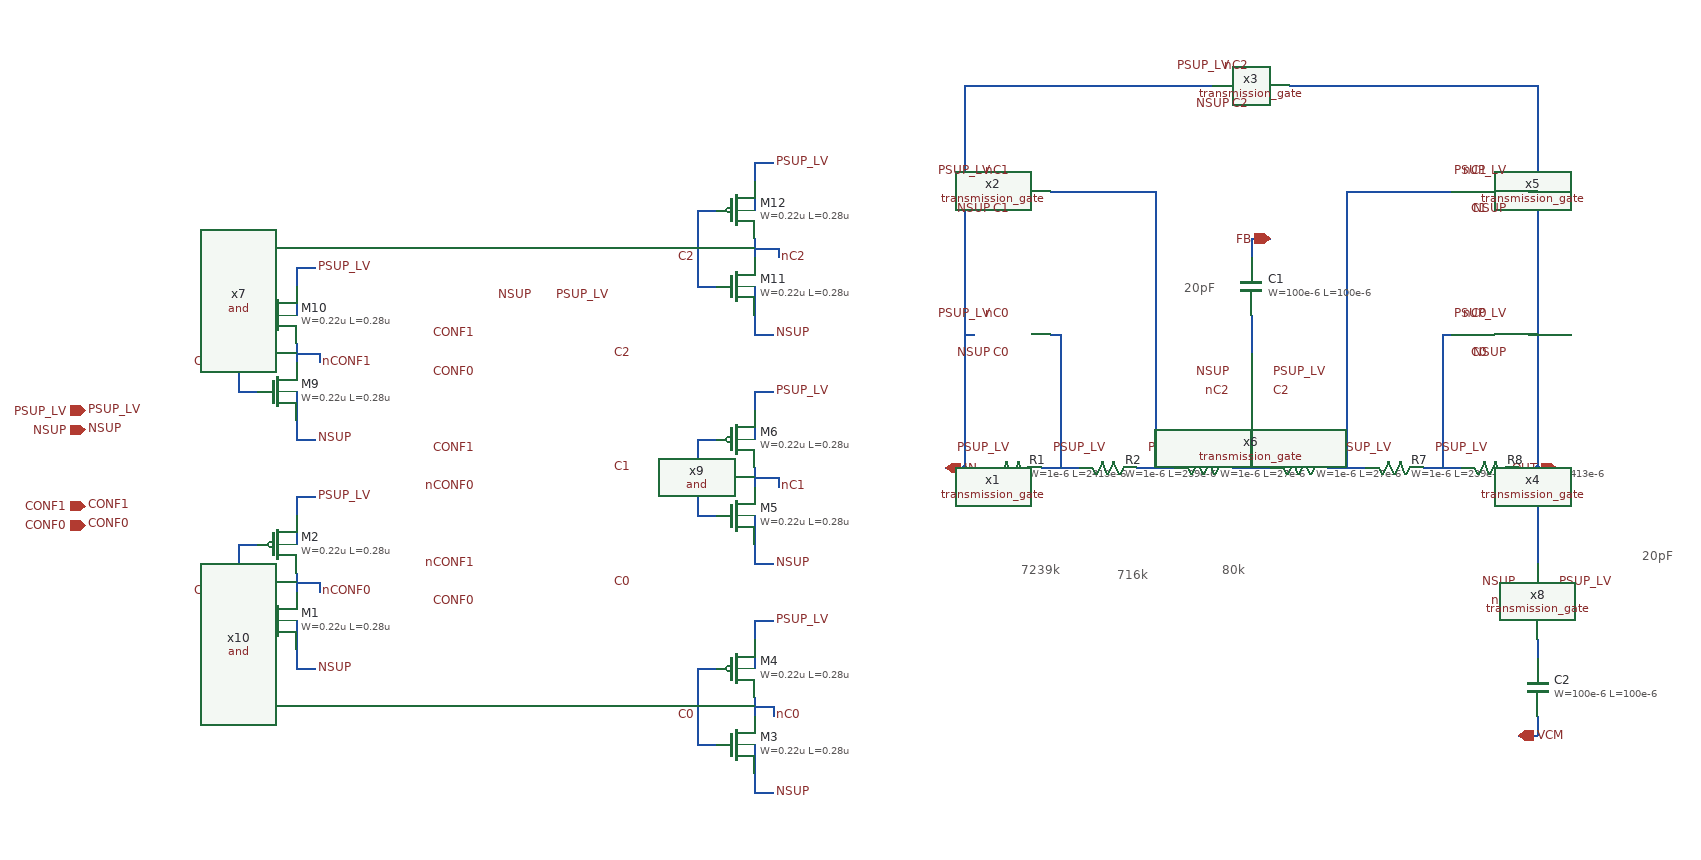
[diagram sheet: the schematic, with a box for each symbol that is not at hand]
v {xschem version=3.4.7 file_version=1.2}
G {}
K {}
V {}
S {}
E {}
T {20pF} 670 -200 0 0 0.4 0.4 {}
T {20pF} 1150 80 0 0 0.4 0.4 {}
T {80k} 710 95 1 0 0.4 0.4 {}
T {716k} 600 100 1 0 0.4 0.4 {}
T {7239k} 500 95 1 0 0.4 0.4 {}
N -320 -160 -300 -160 {lab=CONF1}
N -320 -160 -320 -80 {lab=CONF1}
N -320 -80 -300 -80 {lab=CONF1}
N -260 -130 -260 -110 {lab=nCONF1}
N -260 -120 -235 -120 {lab=nCONF1}
N -235 -120 -235 -110 {lab=nCONF1}
N -260 -210 -240 -210 {lab=PSUP_LV}
N -260 -210 -260 -190 {lab=PSUP_LV}
N -260 -30 -240 -30 {lab=NSUP}
N -260 -50 -260 -30 {lab=NSUP}
N -260 -80 -260 -50 {lab=NSUP}
N -260 -190 -260 -160 {lab=PSUP_LV}
N -320 80 -300 80 {lab=CONF0}
N -320 80 -320 160 {lab=CONF0}
N -320 160 -300 160 {lab=CONF0}
N -260 110 -260 130 {lab=nCONF0}
N -260 120 -235 120 {lab=nCONF0}
N -235 120 -235 130 {lab=nCONF0}
N -260 30 -240 30 {lab=PSUP_LV}
N -260 30 -260 50 {lab=PSUP_LV}
N -260 210 -240 210 {lab=NSUP}
N -260 190 -260 210 {lab=NSUP}
N -260 160 -260 190 {lab=NSUP}
N -260 50 -260 80 {lab=PSUP_LV}
N 740 -240 760 -240 {lab=FB}
N 740 -240 740 -220 {lab=FB}
N 1020 280 1040 280 {lab=VCM}
N 1040 260 1040 280 {lab=VCM}
N 1020 0 1040 0 {lab=OUT}
N 920 0 960 0 {lab=#net1}
N 820 0 860 0 {lab=#net2}
N 720 0 760 0 {lab=#net3}
N 620 0 660 0 {lab=#net4}
N 520 0 560 0 {lab=#net5}
N 1040 0 1040 60 {lab=OUT}
N 1040 0 1060 0 {lab=OUT}
N 440 0 460 0 {lab=IN}
N 160 210 180 210 {lab=C0}
N 160 210 160 290 {lab=C0}
N 160 290 180 290 {lab=C0}
N 220 240 220 260 {lab=nC0}
N 240 250 240 260 {lab=nC0}
N 220 160 240 160 {lab=PSUP_LV}
N 220 160 220 180 {lab=PSUP_LV}
N 220 340 240 340 {lab=NSUP}
N 220 320 220 340 {lab=NSUP}
N 160 -30 180 -30 {lab=C1}
N 160 -30 160 50 {lab=C1}
N 160 50 180 50 {lab=C1}
N 220 0 220 20 {lab=nC1}
N 220 10 245 10 {lab=nC1}
N 245 10 245 20 {lab=nC1}
N 220 -80 240 -80 {lab=PSUP_LV}
N 220 -80 220 -60 {lab=PSUP_LV}
N 220 100 240 100 {lab=NSUP}
N 220 80 220 100 {lab=NSUP}
N 160 -270 180 -270 {lab=C2}
N 160 -270 160 -190 {lab=C2}
N 160 -190 180 -190 {lab=C2}
N 220 -240 220 -220 {lab=nC2}
N 220 -230 245 -230 {lab=nC2}
N 245 -230 245 -220 {lab=nC2}
N 220 -320 240 -320 {lab=PSUP_LV}
N 220 -320 220 -300 {lab=PSUP_LV}
N 220 -140 240 -140 {lab=NSUP}
N 220 -160 220 -140 {lab=NSUP}
N 220 290 220 320 {lab=NSUP}
N 220 180 220 210 {lab=PSUP_LV}
N 220 -60 220 -30 {lab=PSUP_LV}
N 220 50 220 80 {lab=NSUP}
N 220 -300 220 -270 {lab=PSUP_LV}
N 220 -190 220 -160 {lab=NSUP}
N 220 250 240 250 {lab=nC0}
N 420 0 440 0 {lab=IN}
N 440 -270 440 0 {lab=IN}
N 440 -140 450 -140 {lab=IN}
N 440 -400 440 -270 {lab=IN}
N 1040 -400 1040 0 {lab=OUT}
N 440 -400 700 -400 {lab=IN}
N 780 -400 1040 -400 {lab=OUT}
N 440 -290 450 -290 {lab=IN}
N 940 -140 950 -140 {lab=#net1}
N 940 -140 940 0 {lab=#net1}
N 1030 -140 1040 -140 {lab=OUT}
N 840 -270 840 0 {lab=#net2}
N 1030 -290 1040 -290 {lab=OUT}
N 840 -290 950 -290 {lab=#net2}
N 840 -290 840 -270 {lab=#net2}
N 440 -140 450 -140 {lab=IN}
N 440 -290 450 -290 {lab=IN}
N 740 -160 740 -140 {lab=#net6}
N 740 -140 740 -120 {lab=#net6}
N 740 -40 740 0 {lab=#net3}
N 530 -140 540 -140 {lab=#net5}
N 540 -140 540 0 {lab=#net5}
N 640 -290 640 0 {lab=#net4}
N 620 -290 640 -290 {lab=#net4}
N 530 -290 620 -290 {lab=#net4}
N 1040 60 1040 100 {lab=OUT}
N 1040 180 1040 200 {lab=#net7}
C {ipin.sym} -480 -60 0 0 {name=p6 lab=PSUP_LV}
C {ipin.sym} -480 -40 0 0 {name=p7 lab=NSUP}
C {ipin.sym} -480 40 0 0 {name=p4 lab=CONF1}
C {lab_wire.sym} -480 -40 0 1 {name=p12 sig_type=std_logic lab=NSUP}
C {lab_wire.sym} -480 40 0 1 {name=p15 sig_type=std_logic lab=CONF1}
C {lab_wire.sym} -480 -60 0 1 {name=p13 sig_type=std_logic lab=PSUP_LV}
C {ipin.sym} -480 60 0 0 {name=p14 lab=CONF0}
C {lab_wire.sym} -480 60 0 1 {name=p17 sig_type=std_logic lab=CONF0}
C {symbols/nfet_03v3.sym} -280 -80 0 0 {name=M9
L=0.28u
W=0.22u
nf=1
m=1
ad="'int((nf+1)/2) * W/nf * 0.18u'"
pd="'2*int((nf+1)/2) * (W/nf + 0.18u)'"
as="'int((nf+2)/2) * W/nf * 0.18u'"
ps="'2*int((nf+2)/2) * (W/nf + 0.18u)'"
nrd="'0.18u / W'" nrs="'0.18u / W'"
sa=0 sb=0 sd=0
model=nfet_03v3
spiceprefix=X
}
C {symbols/pfet_03v3.sym} -280 -160 0 0 {name=M10
L=0.28u
W=0.22u
nf=1
m=1
ad="'int((nf+1)/2) * W/nf * 0.18u'"
pd="'2*int((nf+1)/2) * (W/nf + 0.18u)'"
as="'int((nf+2)/2) * W/nf * 0.18u'"
ps="'2*int((nf+2)/2) * (W/nf + 0.18u)'"
nrd="'0.18u / W'" nrs="'0.18u / W'"
sa=0 sb=0 sd=0
model=pfet_03v3
spiceprefix=X
}
C {lab_wire.sym} -235 -110 0 1 {name=p50 sig_type=std_logic lab=nCONF1}
C {lab_wire.sym} -240 -210 0 1 {name=p51 sig_type=std_logic lab=PSUP_LV}
C {lab_wire.sym} -240 -30 0 1 {name=p52 sig_type=std_logic lab=NSUP}
C {lab_wire.sym} -320 -110 0 0 {name=p45 sig_type=std_logic lab=CONF1
}
C {symbols/nfet_03v3.sym} -280 160 0 0 {name=M1
L=0.28u
W=0.22u
nf=1
m=1
ad="'int((nf+1)/2) * W/nf * 0.18u'"
pd="'2*int((nf+1)/2) * (W/nf + 0.18u)'"
as="'int((nf+2)/2) * W/nf * 0.18u'"
ps="'2*int((nf+2)/2) * (W/nf + 0.18u)'"
nrd="'0.18u / W'" nrs="'0.18u / W'"
sa=0 sb=0 sd=0
model=nfet_03v3
spiceprefix=X
}
C {symbols/pfet_03v3.sym} -280 80 0 0 {name=M2
L=0.28u
W=0.22u
nf=1
m=1
ad="'int((nf+1)/2) * W/nf * 0.18u'"
pd="'2*int((nf+1)/2) * (W/nf + 0.18u)'"
as="'int((nf+2)/2) * W/nf * 0.18u'"
ps="'2*int((nf+2)/2) * (W/nf + 0.18u)'"
nrd="'0.18u / W'" nrs="'0.18u / W'"
sa=0 sb=0 sd=0
model=pfet_03v3
spiceprefix=X
}
C {lab_wire.sym} -235 130 0 1 {name=p18 sig_type=std_logic lab=nCONF0}
C {lab_wire.sym} -240 30 0 1 {name=p19 sig_type=std_logic lab=PSUP_LV}
C {lab_wire.sym} -240 210 0 1 {name=p20 sig_type=std_logic lab=NSUP}
C {lab_wire.sym} -320 130 0 0 {name=p21 sig_type=std_logic lab=CONF0}
C {iopin.sym} 420 0 0 1 {name=p1 lab=IN}
C {iopin.sym} 1060 0 0 0 {name=p2 lab=OUT}
C {iopin.sym} 760 -240 0 0 {name=p3 lab=FB}
C {symbols/cap_mim_2f0fF.sym} 740 -190 0 0 {name=C1
W=100e-6
L=100e-6
model=cap_mim_2f0fF
spiceprefix=X
m=1}
C {symbols/ppolyf_u_3k.sym} 490 0 1 0 {name=R1
W=1e-6
L=2413e-6
model=ppolyf_u_3k
spiceprefix=X
m=1}
C {symbols/ppolyf_u_3k.sym} 590 0 1 0 {name=R2
W=1e-6
L=239e-6
model=ppolyf_u_3k
spiceprefix=X
m=1}
C {symbols/ppolyf_u_3k.sym} 690 0 1 0 {name=R3
W=1e-6
L=27e-6
model=ppolyf_u_3k
spiceprefix=X
m=1}
C {symbols/ppolyf_u_3k.sym} 790 0 1 0 {name=R6
W=1e-6
L=27e-6
model=ppolyf_u_3k
spiceprefix=X
m=1}
C {symbols/ppolyf_u_3k.sym} 890 0 1 0 {name=R7
W=1e-6
L=239e-6
model=ppolyf_u_3k
spiceprefix=X
m=1}
C {symbols/ppolyf_u_3k.sym} 990 0 1 0 {name=R8
W=1e-6
L=2413e-6
model=ppolyf_u_3k
spiceprefix=X
m=1}
C {symbols/cap_mim_2f0fF.sym} 1040 230 0 0 {name=C2
W=100e-6
L=100e-6
model=cap_mim_2f0fF
spiceprefix=X
m=1}
C {iopin.sym} 1020 280 0 1 {name=p8 lab=VCM}
C {symbols/nfet_03v3.sym} 200 290 0 0 {name=M3
L=0.28u
W=0.22u
nf=1
m=1
ad="'int((nf+1)/2) * W/nf * 0.18u'"
pd="'2*int((nf+1)/2) * (W/nf + 0.18u)'"
as="'int((nf+2)/2) * W/nf * 0.18u'"
ps="'2*int((nf+2)/2) * (W/nf + 0.18u)'"
nrd="'0.18u / W'" nrs="'0.18u / W'"
sa=0 sb=0 sd=0
model=nfet_03v3
spiceprefix=X
}
C {symbols/pfet_03v3.sym} 200 210 0 0 {name=M4
L=0.28u
W=0.22u
nf=1
m=1
ad="'int((nf+1)/2) * W/nf * 0.18u'"
pd="'2*int((nf+1)/2) * (W/nf + 0.18u)'"
as="'int((nf+2)/2) * W/nf * 0.18u'"
ps="'2*int((nf+2)/2) * (W/nf + 0.18u)'"
nrd="'0.18u / W'" nrs="'0.18u / W'"
sa=0 sb=0 sd=0
model=pfet_03v3
spiceprefix=X
}
C {lab_wire.sym} 160 260 0 0 {name=p23 sig_type=std_logic lab=C0}
C {lab_wire.sym} 240 160 0 1 {name=p24 sig_type=std_logic lab=PSUP_LV}
C {lab_wire.sym} 240 340 0 1 {name=p25 sig_type=std_logic lab=NSUP}
C {symbols/nfet_03v3.sym} 200 50 0 0 {name=M5
L=0.28u
W=0.22u
nf=1
m=1
ad="'int((nf+1)/2) * W/nf * 0.18u'"
pd="'2*int((nf+1)/2) * (W/nf + 0.18u)'"
as="'int((nf+2)/2) * W/nf * 0.18u'"
ps="'2*int((nf+2)/2) * (W/nf + 0.18u)'"
nrd="'0.18u / W'" nrs="'0.18u / W'"
sa=0 sb=0 sd=0
model=nfet_03v3
spiceprefix=X
}
C {symbols/pfet_03v3.sym} 200 -30 0 0 {name=M6
L=0.28u
W=0.22u
nf=1
m=1
ad="'int((nf+1)/2) * W/nf * 0.18u'"
pd="'2*int((nf+1)/2) * (W/nf + 0.18u)'"
as="'int((nf+2)/2) * W/nf * 0.18u'"
ps="'2*int((nf+2)/2) * (W/nf + 0.18u)'"
nrd="'0.18u / W'" nrs="'0.18u / W'"
sa=0 sb=0 sd=0
model=pfet_03v3
spiceprefix=X
}
C {lab_wire.sym} 245 20 0 1 {name=p5 sig_type=std_logic lab=nC1}
C {lab_wire.sym} 240 -80 0 1 {name=p28 sig_type=std_logic lab=PSUP_LV}
C {lab_wire.sym} 240 100 0 1 {name=p29 sig_type=std_logic lab=NSUP}
C {symbols/nfet_03v3.sym} 200 -190 0 0 {name=M11
L=0.28u
W=0.22u
nf=1
m=1
ad="'int((nf+1)/2) * W/nf * 0.18u'"
pd="'2*int((nf+1)/2) * (W/nf + 0.18u)'"
as="'int((nf+2)/2) * W/nf * 0.18u'"
ps="'2*int((nf+2)/2) * (W/nf + 0.18u)'"
nrd="'0.18u / W'" nrs="'0.18u / W'"
sa=0 sb=0 sd=0
model=nfet_03v3
spiceprefix=X
}
C {symbols/pfet_03v3.sym} 200 -270 0 0 {name=M12
L=0.28u
W=0.22u
nf=1
m=1
ad="'int((nf+1)/2) * W/nf * 0.18u'"
pd="'2*int((nf+1)/2) * (W/nf + 0.18u)'"
as="'int((nf+2)/2) * W/nf * 0.18u'"
ps="'2*int((nf+2)/2) * (W/nf + 0.18u)'"
nrd="'0.18u / W'" nrs="'0.18u / W'"
sa=0 sb=0 sd=0
model=pfet_03v3
spiceprefix=X
}
C {lab_wire.sym} 160 -220 0 0 {name=p30 sig_type=std_logic lab=C2}
C {lab_wire.sym} 245 -220 0 1 {name=p31 sig_type=std_logic lab=nC2}
C {lab_wire.sym} 240 -320 0 1 {name=p32 sig_type=std_logic lab=PSUP_LV}
C {lab_wire.sym} 240 -140 0 1 {name=p33 sig_type=std_logic lab=NSUP}
C {lab_wire.sym} 160 20 0 0 {name=p27 sig_type=std_logic lab=C1}
C {lab_wire.sym} 240 260 0 1 {name=p22 sig_type=std_logic lab=nC0}
C {blocks/transmission_gate/transmission_gate.sym} 740 -400 0 0 {name=x3}
C {blocks/transmission_gate/transmission_gate.sym} 990 -140 0 1 {name=x4}
C {blocks/transmission_gate/transmission_gate.sym} 990 -290 0 1 {name=x5}
C {lab_wire.sym} 1010 -120 1 1 {name=p11 sig_type=std_logic lab=NSUP}
C {lab_wire.sym} 1010 -160 1 0 {name=p16 sig_type=std_logic lab=PSUP_LV}
C {lab_wire.sym} 1010 -270 1 1 {name=p38 sig_type=std_logic lab=NSUP}
C {lab_wire.sym} 1010 -310 1 0 {name=p39 sig_type=std_logic lab=PSUP_LV}
C {lab_wire.sym} 720 -380 3 0 {name=p44 sig_type=std_logic lab=NSUP}
C {lab_wire.sym} 720 -420 3 1 {name=p46 sig_type=std_logic lab=PSUP_LV}
C {lab_wire.sym} 720 -100 0 0 {name=p47 sig_type=std_logic lab=NSUP}
C {lab_wire.sym} 760 -100 0 1 {name=p48 sig_type=std_logic lab=PSUP_LV}
C {blocks/transmission_gate/transmission_gate.sym} 490 -140 0 0 {name=x1}
C {blocks/transmission_gate/transmission_gate.sym} 490 -290 0 0 {name=x2}
C {lab_wire.sym} 470 -120 3 0 {name=p9 sig_type=std_logic lab=NSUP}
C {lab_wire.sym} 470 -160 3 1 {name=p10 sig_type=std_logic lab=PSUP_LV}
C {lab_wire.sym} 470 -270 3 0 {name=p40 sig_type=std_logic lab=NSUP}
C {lab_wire.sym} 1020 120 0 0 {name=p41 sig_type=std_logic lab=NSUP}
C {lab_wire.sym} 1060 120 0 1 {name=p42 sig_type=std_logic lab=PSUP_LV}
C {lab_wire.sym} 760 -80 0 1 {name=p26 sig_type=std_logic lab=C2}
C {lab_wire.sym} 720 -80 0 0 {name=p43 sig_type=std_logic lab=nC2}
C {lab_wire.sym} 740 -380 1 1 {name=p49 sig_type=std_logic lab=C2}
C {lab_wire.sym} 740 -420 3 1 {name=p53 sig_type=std_logic lab=nC2}
C {lab_wire.sym} 1060 140 0 1 {name=p54 sig_type=std_logic lab=C2}
C {lab_wire.sym} 1020 140 0 0 {name=p55 sig_type=std_logic lab=nC2}
C {blocks/and/and.sym} 0 -120 0 0 {name=x7}
C {lab_wire.sym} -70 -140 0 0 {name=p56 sig_type=std_logic lab=CONF1
}
C {lab_wire.sym} -70 -100 0 0 {name=p57 sig_type=std_logic lab=CONF0}
C {lab_wire.sym} 70 -120 0 1 {name=p58 sig_type=std_logic lab=C2}
C {blocks/and/and.sym} 0 0 0 0 {name=x9}
C {blocks/and/and.sym} 0 120 0 0 {name=x10}
C {lab_wire.sym} -70 140 0 0 {name=p61 sig_type=std_logic lab=CONF0}
C {lab_wire.sym} -70 -20 0 0 {name=p62 sig_type=std_logic lab=CONF1
}
C {lab_wire.sym} -70 100 0 0 {name=p63 sig_type=std_logic lab=nCONF1}
C {lab_wire.sym} -70 20 0 0 {name=p64 sig_type=std_logic lab=nCONF0}
C {lab_wire.sym} 10 -180 0 1 {name=p59 sig_type=std_logic lab=PSUP_LV}
C {lab_wire.sym} -10 -180 0 0 {name=p60 sig_type=std_logic lab=NSUP}
C {lab_wire.sym} 70 120 0 1 {name=p34 sig_type=std_logic lab=C0}
C {lab_wire.sym} 490 -120 1 1 {name=p35 sig_type=std_logic lab=C0}
C {lab_wire.sym} 990 -120 3 0 {name=p36 sig_type=std_logic lab=C0}
C {lab_wire.sym} 490 -160 1 0 {name=p37 sig_type=std_logic lab=nC0}
C {lab_wire.sym} 990 -160 3 1 {name=p65 sig_type=std_logic lab=nC0}
C {lab_wire.sym} 70 0 0 1 {name=p66 sig_type=std_logic lab=C1}
C {lab_wire.sym} 490 -270 1 1 {name=p67 sig_type=std_logic lab=C1}
C {lab_wire.sym} 990 -270 3 0 {name=p68 sig_type=std_logic lab=C1}
C {lab_wire.sym} 490 -310 1 0 {name=p69 sig_type=std_logic lab=nC1}
C {lab_wire.sym} 990 -310 3 1 {name=p70 sig_type=std_logic lab=nC1}
C {lab_wire.sym} 590 -20 3 1 {name=p72 sig_type=std_logic lab=PSUP_LV}
C {lab_wire.sym} 690 -20 3 1 {name=p73 sig_type=std_logic lab=PSUP_LV}
C {lab_wire.sym} 790 -20 1 0 {name=p74 sig_type=std_logic lab=PSUP_LV}
C {lab_wire.sym} 490 -20 3 1 {name=p75 sig_type=std_logic lab=PSUP_LV}
C {lab_wire.sym} 890 -20 1 0 {name=p76 sig_type=std_logic lab=PSUP_LV}
C {lab_wire.sym} 990 -20 1 0 {name=p77 sig_type=std_logic lab=PSUP_LV}
C {lab_wire.sym} 470 -310 3 1 {name=p71 sig_type=std_logic lab=PSUP_LV}
C {blocks/transmission_gate/transmission_gate.sym} 740 -80 1 0 {name=x6}
C {blocks/transmission_gate/transmission_gate.sym} 1040 140 1 0 {name=x8}
